One B-rep face of a CAD part: STEP entity #1051.
In plain terms, the cylindrical face has radius 21 mm (diameter 42 mm), a partial arc.
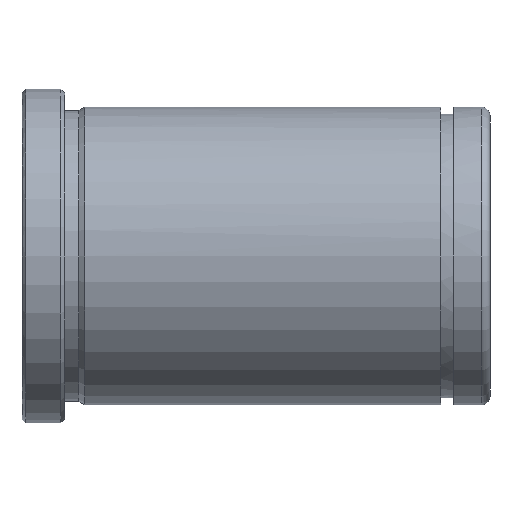
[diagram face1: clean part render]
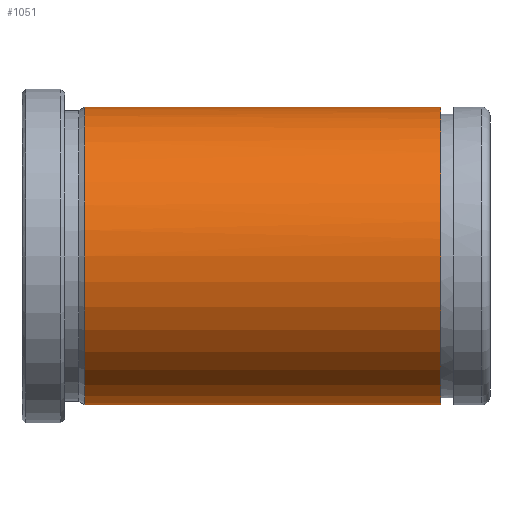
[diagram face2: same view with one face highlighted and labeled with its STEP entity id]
Its self-contained STEP definition (entity closure, numbers rounded to 3 decimals):
#851=CARTESIAN_POINT('Vertex',(8.866,0.,-21.)) ;
#858=CARTESIAN_POINT('Vertex',(8.866,0.,21.)) ;
#887=CARTESIAN_POINT('Axis2P3D Location',(8.866,0.,0.)) ;
#891=CARTESIAN_POINT('Vertex',(8.866,-21.,0.)) ;
#894=CARTESIAN_POINT('Axis2P3D Location',(8.866,0.,0.)) ;
#985=CARTESIAN_POINT('Line Origine',(132.,0.,21.)) ;
#989=CARTESIAN_POINT('Vertex',(59.05,0.,21.)) ;
#1006=CARTESIAN_POINT('Vertex',(59.05,0.,-21.)) ;
#1009=CARTESIAN_POINT('Line Origine',(132.,0.,-21.)) ;
#1023=CARTESIAN_POINT('Axis2P3D Location',(132.,0.,0.)) ;
#1028=CARTESIAN_POINT('Axis2P3D Location',(59.05,0.,0.)) ;
#1032=CARTESIAN_POINT('Vertex',(59.05,-21.,0.)) ;
#1036=CARTESIAN_POINT('Control Point',(59.05,0.,21.)) ;
#1037=CARTESIAN_POINT('Control Point',(59.05,-6.597,21.)) ;
#1038=CARTESIAN_POINT('Control Point',(59.05,-13.201,18.417)) ;
#1039=CARTESIAN_POINT('Control Point',(59.05,-18.417,13.201)) ;
#1040=CARTESIAN_POINT('Control Point',(59.05,-21.,6.597)) ;
#1041=CARTESIAN_POINT('Control Point',(59.05,-21.,0.)) ;
#888=DIRECTION('Axis2P3D Direction',(1.,0.,-0.)) ;
#895=DIRECTION('Axis2P3D Direction',(1.,0.,-0.)) ;
#986=DIRECTION('Vector Direction',(-1.,0.,0.)) ;
#1010=DIRECTION('Vector Direction',(-1.,0.,0.)) ;
#1024=DIRECTION('Axis2P3D Direction',(-1.,-0.,-0.)) ;
#1025=DIRECTION('Axis2P3D XDirection',(0.,0.,-1.)) ;
#1029=DIRECTION('Axis2P3D Direction',(-1.,-0.,-0.)) ;
#889=AXIS2_PLACEMENT_3D('Circle Axis2P3D',#887,#888,$) ;
#896=AXIS2_PLACEMENT_3D('Circle Axis2P3D',#894,#895,$) ;
#1026=AXIS2_PLACEMENT_3D('Cylinder Axis2P3D',#1023,#1024,#1025) ;
#1030=AXIS2_PLACEMENT_3D('Circle Axis2P3D',#1028,#1029,$) ;
#1044=ORIENTED_EDGE('',*,*,#1013,.T.) ;
#1045=ORIENTED_EDGE('',*,*,#1034,.F.) ;
#1046=ORIENTED_EDGE('',*,*,#1042,.F.) ;
#1047=ORIENTED_EDGE('',*,*,#991,.T.) ;
#1048=ORIENTED_EDGE('',*,*,#898,.T.) ;
#1049=ORIENTED_EDGE('',*,*,#893,.T.) ;
#987=VECTOR('Line Direction',#986,1.) ;
#1011=VECTOR('Line Direction',#1010,1.) ;
#1051=ADVANCED_FACE('553-30X66',(#1050),#1027,.T.) ;
#1035=B_SPLINE_CURVE_WITH_KNOTS('',5,(#1036,#1037,#1038,#1039,#1040,#1041),.UNSPECIFIED.,.F.,.U.,(6,6),(-16.493,16.493),.UNSPECIFIED.) ;
#890=CIRCLE('generated circle',#889,21.) ;
#897=CIRCLE('generated circle',#896,21.) ;
#1031=CIRCLE('generated circle',#1030,21.) ;
#1027=CYLINDRICAL_SURFACE('generated cylinder',#1026,21.) ;
#893=EDGE_CURVE('',#892,#852,#890,.T.) ;
#898=EDGE_CURVE('',#859,#892,#897,.T.) ;
#991=EDGE_CURVE('',#990,#859,#988,.T.) ;
#1013=EDGE_CURVE('',#852,#1007,#1012,.F.) ;
#1034=EDGE_CURVE('',#1033,#1007,#1031,.F.) ;
#1042=EDGE_CURVE('',#990,#1033,#1035,.T.) ;
#1043=EDGE_LOOP('',(#1044,#1045,#1046,#1047,#1048,#1049)) ;
#1050=FACE_OUTER_BOUND('',#1043,.T.) ;
#988=LINE('Line',#985,#987) ;
#1012=LINE('Line',#1009,#1011) ;
#852=VERTEX_POINT('',#851) ;
#859=VERTEX_POINT('',#858) ;
#892=VERTEX_POINT('',#891) ;
#990=VERTEX_POINT('',#989) ;
#1007=VERTEX_POINT('',#1006) ;
#1033=VERTEX_POINT('',#1032) ;
